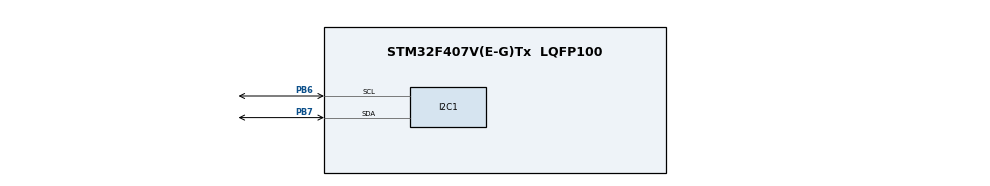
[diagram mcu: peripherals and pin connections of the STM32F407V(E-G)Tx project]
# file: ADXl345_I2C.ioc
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I2C1.I2C_Mode=I2C_Fast
Mcu.Family=STM32F4
Mcu.Name=STM32F407V(E-G)Tx
Mcu.Package=LQFP100
NVIC.PriorityGroup=NVIC_PRIORITYGROUP_4
PB6.Mode=I2C
PB6.Signal=I2C1_SCL
PB7.Mode=I2C
PB7.Signal=I2C1_SDA
ProjectManager.HeapSize=0x200
ProjectManager.StackSize=0x400
ProjectManager.TargetToolchain=STM32CubeIDE
RCC.48MHZClocksFreq_Value=84000000
RCC.AHBFreq_Value=168000000
RCC.APB1CLKDivider=RCC_HCLK_DIV4
RCC.APB1Freq_Value=42000000
RCC.APB1TimFreq_Value=84000000
RCC.APB2CLKDivider=RCC_HCLK_DIV2
RCC.APB2Freq_Value=84000000
RCC.APB2TimFreq_Value=168000000
RCC.CortexFreq_Value=168000000
RCC.HCLKFreq_Value=168000000
RCC.HSE_VALUE=25000000
RCC.HSI_VALUE=16000000
RCC.LSE_VALUE=32768
RCC.PLLM=8
RCC.PLLN=168
RCC.SYSCLKFreq_VALUE=168000000
RCC.SYSCLKSource=RCC_SYSCLKSOURCE_PLLCLK
RCC.VCOOutputFreq_Value=336000000
board=custom

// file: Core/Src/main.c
/* USER CODE BEGIN Header */
/**
  ******************************************************************************
  * @file           : main.c
  * @brief          : Main program body
  ******************************************************************************
  * @attention
  *
  * <h2><center>&copy; Copyright (c) 2019 STMicroelectronics.
  * All rights reserved.</center></h2>
  *
  * This software component is licensed by ST under BSD 3-Clause license,
  * the "License"; You may not use this file except in compliance with the
  * License. You may obtain a copy of the License at:
  *                        opensource.org/licenses/BSD-3-Clause
  *
  ******************************************************************************
  */
/* USER CODE END Header */

#include "main.h"

/* USER CODE BEGIN Includes */

#include "ADXL345_i2c.h"

/* ADXL345 in datasheetinde I2C nin adresi 0x53 olarak vermiş. Aşağıdaki yazdığımız
algoritma ile bunu kesinleştirmek istiyorum. bknz. Scan_I2C_Address function*/

//////////////#define ADXL_ADDRESS 0xA6	// 0x53 << 1 şeklinde de ifade edilebilir.

/* USER CODE END Includes */

I2C_HandleTypeDef hi2c1;

/* USER CODE BEGIN PV */

int16_t a,b,c;

/* USER CODE END PV */

void SystemClock_Config(void);
static void MX_GPIO_Init(void);
static void MX_I2C1_Init(void);
/* USER CODE BEGIN PFP */

//void Scan_I2C_Address();
//void ADXL_Init();
//void ADXL_Write(uint8_t reg, uint8_t value);
//void ADXL_Read(uint8_t reg, uint8_t numberOfBytes);

/* USER CODE END PFP */

int main(void)
{

  /* MCU Configuration--------------------------------------------------------*/

  /* Reset of all peripherals, Initializes the Flash interface and the Systick. */
  HAL_Init();

  /* Configure the system clock */
  SystemClock_Config();

  /* Initialize all configured peripherals */
  MX_GPIO_Init();
  MX_I2C1_Init();
  /* USER CODE BEGIN 2 */

  Scan_I2C_Address();

  ADXL_Init();

  /* USER CODE END 2 */

  /* Infinite loop */
  while (1)
  {

    /* USER CODE BEGIN 3 */

	values(&a,&b,&c);

  }
  /* USER CODE END 3 */
}

void SystemClock_Config(void)
{
  RCC_OscInitTypeDef RCC_OscInitStruct = {0};
  RCC_ClkInitTypeDef RCC_ClkInitStruct = {0};

  /** Configure the main internal regulator output voltage
  */
  __HAL_RCC_PWR_CLK_ENABLE();
  __HAL_PWR_VOLTAGESCALING_CONFIG(PWR_REGULATOR_VOLTAGE_SCALE1);
  /** Initializes the CPU, AHB and APB busses clocks
  */
  RCC_OscInitStruct.OscillatorType = RCC_OSCILLATORTYPE_HSE;
  RCC_OscInitStruct.HSEState = RCC_HSE_ON;
  RCC_OscInitStruct.PLL.PLLState = RCC_PLL_ON;
  RCC_OscInitStruct.PLL.PLLSource = RCC_PLLSOURCE_HSE;
  RCC_OscInitStruct.PLL.PLLM = 4;
  RCC_OscInitStruct.PLL.PLLN = 168;
  RCC_OscInitStruct.PLL.PLLP = RCC_PLLP_DIV2;
  RCC_OscInitStruct.PLL.PLLQ = 4;
  if (HAL_RCC_OscConfig(&RCC_OscInitStruct) != HAL_OK)
  {
    Error_Handler();
  }
  /** Initializes the CPU, AHB and APB busses clocks
  */
  RCC_ClkInitStruct.ClockType = RCC_CLOCKTYPE_HCLK|RCC_CLOCKTYPE_SYSCLK
                              |RCC_CLOCKTYPE_PCLK1|RCC_CLOCKTYPE_PCLK2;
  RCC_ClkInitStruct.SYSCLKSource = RCC_SYSCLKSOURCE_PLLCLK;
  RCC_ClkInitStruct.AHBCLKDivider = RCC_SYSCLK_DIV1;
  RCC_ClkInitStruct.APB1CLKDivider = RCC_HCLK_DIV4;
  RCC_ClkInitStruct.APB2CLKDivider = RCC_HCLK_DIV2;

  if (HAL_RCC_ClockConfig(&RCC_ClkInitStruct, FLASH_LATENCY_5) != HAL_OK)
  {
    Error_Handler();
  }
}

static void MX_I2C1_Init(void)
{

  hi2c1.Instance = I2C1;
  hi2c1.Init.ClockSpeed = 100000;
  hi2c1.Init.DutyCycle = I2C_DUTYCYCLE_2;
  hi2c1.Init.OwnAddress1 = 0;
  hi2c1.Init.AddressingMode = I2C_ADDRESSINGMODE_7BIT;
  hi2c1.Init.DualAddressMode = I2C_DUALADDRESS_DISABLE;
  hi2c1.Init.OwnAddress2 = 0;
  hi2c1.Init.GeneralCallMode = I2C_GENERALCALL_DISABLE;
  hi2c1.Init.NoStretchMode = I2C_NOSTRETCH_DISABLE;
  if (HAL_I2C_Init(&hi2c1) != HAL_OK)
  {
    Error_Handler();
  }

}

static void MX_GPIO_Init(void)
{
  GPIO_InitTypeDef GPIO_InitStruct = {0};

  /* GPIO Ports Clock Enable */
  __HAL_RCC_GPIOH_CLK_ENABLE();
  __HAL_RCC_GPIOD_CLK_ENABLE();
  __HAL_RCC_GPIOB_CLK_ENABLE();

  /*Configure GPIO pin Output Level */
  HAL_GPIO_WritePin(GPIOD, GPIO_PIN_11, GPIO_PIN_RESET);

  /*Configure GPIO pin : PD11 */
  GPIO_InitStruct.Pin = GPIO_PIN_11;
  GPIO_InitStruct.Mode = GPIO_MODE_OUTPUT_PP;
  GPIO_InitStruct.Pull = GPIO_NOPULL;
  GPIO_InitStruct.Speed = GPIO_SPEED_FREQ_LOW;
  HAL_GPIO_Init(GPIOD, &GPIO_InitStruct);

}

void Error_Handler(void)
{
}

/************************ (C) COPYRIGHT STMicroelectronics *****END OF FILE****/
